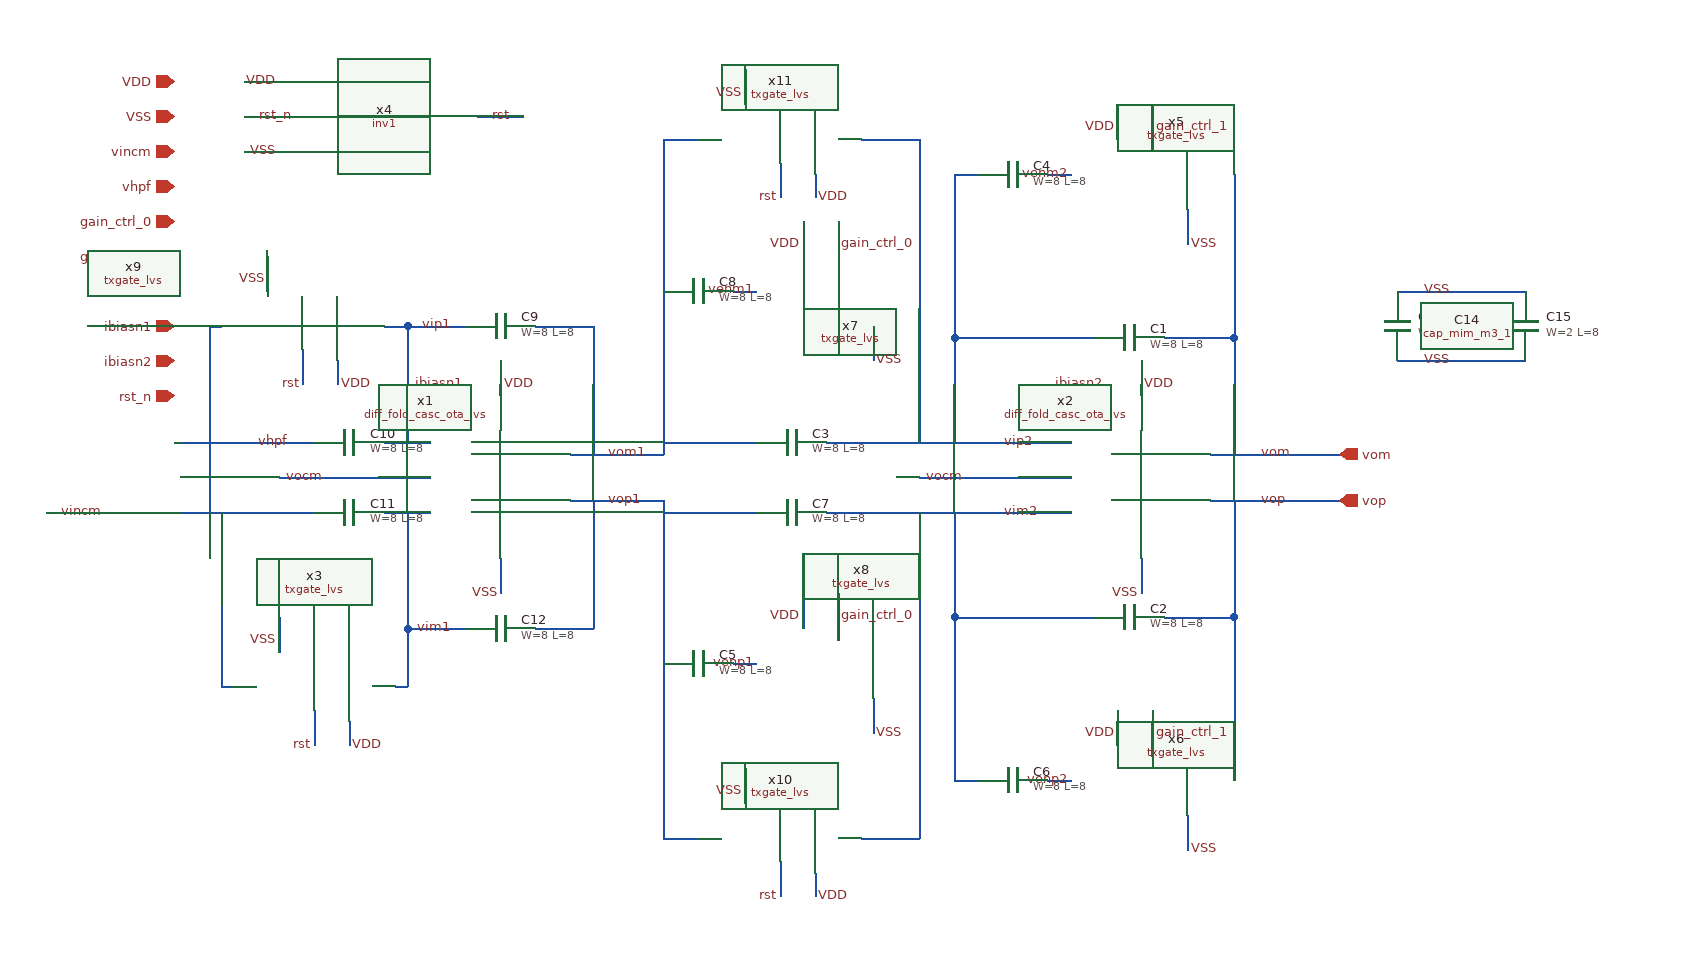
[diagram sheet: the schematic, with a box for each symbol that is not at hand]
v {xschem version=2.9.9 file_version=1.2 }
G {}
K {}
V {}
S {}
E {}
N 970 -630 1030 -630 { lab=vom}
N 1030 -630 1030 -530 { lab=vom}
N 1010 -490 1120 -490 { lab=vop}
N 1010 -530 1120 -530 { lab=vom}
N 790 -630 910 -630 { lab=vip2}
N 790 -630 790 -540 { lab=vip2}
N 790 -770 810 -770 { lab=vip2}
N 790 -770 790 -630 { lab=vip2}
N 1030 -770 1030 -630 { lab=vom}
N 680 -540 890 -540 { lab=vip2}
N 760 -670 760 -540 { lab=vip2}
N 970 -390 1030 -390 { lab=vop}
N 1030 -490 1030 -390 { lab=vop}
N 790 -390 910 -390 { lab=vim2}
N 790 -480 790 -390 { lab=vim2}
N 790 -250 810 -250 { lab=vim2}
N 790 -390 790 -250 { lab=vim2}
N 1030 -390 1030 -250 { lab=vop}
N 680 -480 890 -480 { lab=vim2}
N 760 -480 760 -350 { lab=vim2}
N 300 -540 340 -540 { lab=vip1}
N 300 -480 340 -480 { lab=vim1}
N 320 -480 320 -380 { lab=vim1}
N 320 -380 370 -380 { lab=vim1}
N 320 -640 320 -540 { lab=vip1}
N 320 -640 370 -640 { lab=vip1}
N 210 -510 340 -510 { lab=vocm}
N 430 -640 480 -640 { lab=vom1}
N 480 -640 480 -530 { lab=vom1}
N 430 -380 480 -380 { lab=vop1}
N 480 -490 480 -380 { lab=vop1}
N 460 -530 540 -530 { lab=vom1}
N 460 -490 540 -490 { lab=vop1}
N 120 -540 240 -540 { lab=vhpf}
N 10 -480 240 -480 { lab=vincm}
N 760 -510 890 -510 { lab=vocm}
N 540 -540 620 -540 { lab=vom1}
N 540 -480 620 -480 { lab=vop1}
N 540 -670 540 -530 { lab=vom1}
N 540 -490 540 -350 { lab=vop1}
N 870 -770 890 -770 { lab=venm2}
N 960 -830 960 -790 { lab=gain_ctrl_1}
N 990 -740 990 -710 { lab=VSS}
N 930 -830 930 -800 { lab=VDD}
N 870 -250 890 -250 { lab=venp2}
N 960 -310 960 -270 { lab=gain_ctrl_1}
N 990 -220 990 -190 { lab=VSS}
N 930 -310 930 -280 { lab=VDD}
N 690 -730 690 -690 { lab=gain_ctrl_0}
N 720 -640 720 -610 { lab=VSS}
N 660 -730 660 -700 { lab=VDD}
N 600 -670 620 -670 { lab=venm1}
N 690 -410 690 -370 { lab=gain_ctrl_0}
N 720 -320 720 -290 { lab=VSS}
N 660 -410 660 -380 { lab=VDD}
N 600 -350 620 -350 { lab=venp1}
N 330 -590 370 -590 { lab=ibiasn1}
N 400 -610 400 -580 { lab=VDD}
N 400 -440 400 -410 { lab=VSS}
N 880 -590 920 -590 { lab=ibiasn2}
N 950 -610 950 -580 { lab=VDD}
N 950 -440 950 -410 { lab=VSS}
N 1170 -670 1280 -670 { lab=VSS}
N 1170 -610 1280 -610 { lab=VSS}
N 310 -330 320 -330 { lab=vim1}
N 160 -330 170 -330 { lab=vincm}
N 210 -390 210 -360 { lab=VSS}
N 270 -300 270 -280 { lab=VDD}
N 240 -310 240 -280 { lab=rst}
N 380 -820 420 -820 { lab=rst}
N 180 -850 220 -850 { lab=VDD}
N 180 -790 220 -790 { lab=VSS}
N 180 -820 220 -820 { lab=rst_n}
N 320 -380 320 -330 { lab=vim1}
N 160 -480 160 -330 { lab=vincm}
N 300 -640 310 -640 { lab=vip1}
N 150 -640 160 -640 { lab=vincm}
N 200 -700 200 -670 { lab=VSS}
N 260 -610 260 -590 { lab=VDD}
N 230 -620 230 -590 { lab=rst}
N 310 -640 320 -640 { lab=vip1}
N 150 -640 150 -480 { lab=vincm}
N 710 -200 720 -200 { lab=vim2}
N 560 -200 570 -200 { lab=vop1}
N 610 -260 610 -230 { lab=VSS}
N 670 -170 670 -150 { lab=VDD}
N 640 -180 640 -150 { lab=rst}
N 720 -200 730 -200 { lab=vim2}
N 730 -200 760 -200 { lab=vim2}
N 760 -350 760 -200 { lab=vim2}
N 540 -200 560 -200 { lab=vop1}
N 540 -350 540 -200 { lab=vop1}
N 710 -800 720 -800 { lab=vip2}
N 560 -800 570 -800 { lab=vom1}
N 610 -860 610 -830 { lab=VSS}
N 670 -770 670 -750 { lab=VDD}
N 640 -780 640 -750 { lab=rst}
N 720 -800 730 -800 { lab=vip2}
N 730 -800 760 -800 { lab=vip2}
N 760 -800 760 -670 { lab=vip2}
N 540 -800 560 -800 { lab=vom1}
N 540 -800 540 -670 { lab=vom1}
C {devices/title.sym} 160 -30 0 0 {name=l1 author="Nikhil Poole"}
C {devices/lab_wire.sym} 1050 -530 0 1 {name=l7 sig_type=std_logic lab=vom}
C {devices/lab_wire.sym} 1050 -490 0 1 {name=l8 sig_type=std_logic lab=vop}
C {devices/lab_wire.sym} 360 -640 0 0 {name=l4 sig_type=std_logic lab=vip1}
C {devices/lab_wire.sym} 360 -380 2 1 {name=l5 sig_type=std_logic lab=vim1}
C {devices/lab_wire.sym} 60 -480 0 0 {name=l3 sig_type=std_logic lab=vincm}
C {devices/lab_wire.sym} 490 -530 0 1 {name=l30 sig_type=std_logic lab=vom1}
C {devices/lab_wire.sym} 490 -490 0 1 {name=l31 sig_type=std_logic lab=vop1}
C {devices/lab_wire.sym} 250 -510 0 0 {name=l33 sig_type=std_logic lab=vocm}
C {devices/lab_wire.sym} 800 -510 0 0 {name=l2 sig_type=std_logic lab=vocm}
C {devices/lab_wire.sym} 220 -540 0 0 {name=l29 sig_type=std_logic lab=vhpf}
C {devices/lab_wire.sym} 830 -480 0 1 {name=l34 sig_type=std_logic lab=vim2}
C {devices/lab_wire.sym} 830 -540 0 1 {name=l35 sig_type=std_logic lab=vip2}
C {/home/users/nhpoole/ee272b/ee272b_mixed_signal_mmwave_accelerator/designs/txgate_lvs.sym} 960 -770 0 0 {name=x5}
C {devices/lab_wire.sym} 890 -770 0 0 {name=l25 sig_type=std_logic lab=venm2}
C {devices/lab_wire.sym} 960 -810 0 1 {name=l27 sig_type=std_logic lab=gain_ctrl_1}
C {devices/lab_wire.sym} 990 -710 0 1 {name=l39 sig_type=std_logic lab=VSS}
C {devices/lab_wire.sym} 930 -810 0 0 {name=l40 sig_type=std_logic lab=VDD}
C {/home/users/nhpoole/ee272b/ee272b_mixed_signal_mmwave_accelerator/designs/txgate_lvs.sym} 960 -250 0 0 {name=x6}
C {devices/lab_wire.sym} 890 -250 0 0 {name=l12 sig_type=std_logic lab=venp2}
C {devices/lab_wire.sym} 960 -290 0 1 {name=l14 sig_type=std_logic lab=gain_ctrl_1}
C {devices/lab_wire.sym} 990 -190 0 1 {name=l26 sig_type=std_logic lab=VSS}
C {devices/lab_wire.sym} 930 -290 0 0 {name=l28 sig_type=std_logic lab=VDD}
C {/home/users/nhpoole/ee272b/ee272b_mixed_signal_mmwave_accelerator/designs/txgate_lvs.sym} 690 -670 0 0 {name=x7}
C {devices/lab_wire.sym} 690 -710 0 1 {name=l6 sig_type=std_logic lab=gain_ctrl_0}
C {devices/lab_wire.sym} 720 -610 0 1 {name=l11 sig_type=std_logic lab=VSS}
C {devices/lab_wire.sym} 660 -710 0 0 {name=l19 sig_type=std_logic lab=VDD}
C {devices/lab_wire.sym} 620 -670 0 0 {name=l20 sig_type=std_logic lab=venm1}
C {/home/users/nhpoole/ee272b/ee272b_mixed_signal_mmwave_accelerator/designs/txgate_lvs.sym} 690 -350 0 0 {name=x8}
C {devices/lab_wire.sym} 690 -390 0 1 {name=l15 sig_type=std_logic lab=gain_ctrl_0}
C {devices/lab_wire.sym} 720 -290 0 1 {name=l16 sig_type=std_logic lab=VSS}
C {devices/lab_wire.sym} 660 -390 0 0 {name=l21 sig_type=std_logic lab=VDD}
C {devices/lab_wire.sym} 620 -350 0 0 {name=l22 sig_type=std_logic lab=venp1}
C {devices/ipin.sym} 120 -850 0 0 {name=p1 lab=VDD}
C {devices/ipin.sym} 120 -820 0 0 {name=p2 lab=VSS}
C {devices/ipin.sym} 120 -790 0 0 {name=p3 lab=vincm}
C {devices/ipin.sym} 120 -760 0 0 {name=p4 lab=vhpf}
C {devices/ipin.sym} 120 -730 0 0 {name=p5 lab=gain_ctrl_0}
C {devices/ipin.sym} 120 -700 0 0 {name=p6 lab=gain_ctrl_1}
C {devices/ipin.sym} 120 -670 0 0 {name=p7 lab=vocm}
C {devices/ipin.sym} 120 -640 0 0 {name=p8 lab=ibiasn1}
C {devices/lab_wire.sym} 370 -590 0 0 {name=l9 sig_type=std_logic lab=ibiasn1}
C {devices/lab_wire.sym} 400 -410 0 0 {name=l13 sig_type=std_logic lab=VSS}
C {devices/lab_wire.sym} 400 -590 0 1 {name=l17 sig_type=std_logic lab=VDD}
C {devices/lab_wire.sym} 920 -590 0 0 {name=l18 sig_type=std_logic lab=ibiasn2}
C {devices/lab_wire.sym} 950 -410 0 0 {name=l23 sig_type=std_logic lab=VSS}
C {devices/lab_wire.sym} 950 -590 0 1 {name=l24 sig_type=std_logic lab=VDD}
C {sky130_fd_pr/cap_mim_m3_1.sym} 940 -630 1 0 {name=C1 model=cap_mim_m3_1 W=8 L=8 MF=2 spiceprefix=X}
C {sky130_fd_pr/cap_mim_m3_1.sym} 940 -390 1 0 {name=C2 model=cap_mim_m3_1 W=8 L=8 MF=2 spiceprefix=X}
C {sky130_fd_pr/cap_mim_m3_1.sym} 840 -770 1 0 {name=C4 model=cap_mim_m3_1 W=8 L=8 MF=6 spiceprefix=X}
C {sky130_fd_pr/cap_mim_m3_1.sym} 840 -250 1 0 {name=C6 model=cap_mim_m3_1 W=8 L=8 MF=6 spiceprefix=X}
C {sky130_fd_pr/cap_mim_m3_1.sym} 570 -350 1 0 {name=C5 model=cap_mim_m3_1 W=8 L=8 MF=4 spiceprefix=X}
C {sky130_fd_pr/cap_mim_m3_1.sym} 650 -480 1 0 {name=C7 model=cap_mim_m3_1 W=8 L=8 MF=4 spiceprefix=X}
C {sky130_fd_pr/cap_mim_m3_1.sym} 650 -540 1 0 {name=C3 model=cap_mim_m3_1 W=8 L=8 MF=4 spiceprefix=X}
C {sky130_fd_pr/cap_mim_m3_1.sym} 570 -670 1 0 {name=C8 model=cap_mim_m3_1 W=8 L=8 MF=4 spiceprefix=X}
C {sky130_fd_pr/cap_mim_m3_1.sym} 400 -640 1 0 {name=C9 model=cap_mim_m3_1 W=8 L=8 MF=4 spiceprefix=X}
C {sky130_fd_pr/cap_mim_m3_1.sym} 270 -540 1 0 {name=C10 model=cap_mim_m3_1 W=8 L=8 MF=4 spiceprefix=X}
C {sky130_fd_pr/cap_mim_m3_1.sym} 270 -480 1 0 {name=C11 model=cap_mim_m3_1 W=8 L=8 MF=4 spiceprefix=X}
C {sky130_fd_pr/cap_mim_m3_1.sym} 400 -380 1 0 {name=C12 model=cap_mim_m3_1 W=8 L=8 MF=4 spiceprefix=X}
C {sky130_fd_pr/cap_mim_m3_1.sym} 1170 -640 0 0 {name=C13 model=cap_mim_m3_1 W=12 L=2 MF=20 spiceprefix=X}
C {sky130_fd_pr/cap_mim_m3_1.sym} 1230 -640 0 0 {name=C14 model=cap_mim_m3_1 W=8 L=2 MF=22 spiceprefix=X}
C {sky130_fd_pr/cap_mim_m3_1.sym} 1280 -640 0 0 {name=C15 model=cap_mim_m3_1 W=2 L=8 MF=24 spiceprefix=X}
C {devices/lab_wire.sym} 1190 -670 0 1 {name=l10 sig_type=std_logic lab=VSS}
C {devices/lab_wire.sym} 1190 -610 2 0 {name=l32 sig_type=std_logic lab=VSS}
C {devices/opin.sym} 1120 -530 0 0 {name=p9 lab=vom}
C {devices/opin.sym} 1120 -490 0 0 {name=p10 lab=vop}
C {/home/users/nhpoole/ee272b/ee272b_mixed_signal_mmwave_accelerator/designs/diff_fold_casc_ota_lvs.sym} 400 -510 0 0 {name=x1}
C {/home/users/nhpoole/ee272b/ee272b_mixed_signal_mmwave_accelerator/designs/diff_fold_casc_ota_lvs.sym} 950 -510 0 0 {name=x2}
C {devices/ipin.sym} 120 -610 0 0 {name=p11 lab=ibiasn2}
C {/home/users/nhpoole/ee272b/ee272b_mixed_signal_mmwave_accelerator/designs/txgate_lvs.sym} 240 -330 2 0 {name=x3}
C {devices/lab_wire.sym} 210 -370 0 0 {name=l36 sig_type=std_logic lab=VSS}
C {devices/lab_wire.sym} 270 -280 0 1 {name=l37 sig_type=std_logic lab=VDD}
C {devices/lab_wire.sym} 240 -280 0 0 {name=l38 sig_type=std_logic lab=rst}
C {/home/users/nhpoole/ee272b/ee272b_mixed_signal_mmwave_accelerator/designs/inv1.sym} 270 -820 0 0 {name=x4}
C {devices/lab_wire.sym} 390 -820 0 1 {name=l41 sig_type=std_logic lab=rst}
C {devices/lab_wire.sym} 190 -820 0 1 {name=l42 sig_type=std_logic lab=rst_n}
C {devices/lab_wire.sym} 210 -850 0 0 {name=l43 sig_type=std_logic lab=VDD}
C {devices/lab_wire.sym} 210 -790 0 0 {name=l44 sig_type=std_logic lab=VSS}
C {devices/ipin.sym} 120 -580 0 0 {name=p12 lab=rst_n}
C {/home/users/nhpoole/ee272b/ee272b_mixed_signal_mmwave_accelerator/designs/txgate_lvs.sym} 230 -640 2 0 {name=x9}
C {devices/lab_wire.sym} 200 -680 0 0 {name=l45 sig_type=std_logic lab=VSS}
C {devices/lab_wire.sym} 260 -590 0 1 {name=l46 sig_type=std_logic lab=VDD}
C {devices/lab_wire.sym} 230 -590 0 0 {name=l47 sig_type=std_logic lab=rst}
C {/home/users/nhpoole/ee272b/ee272b_mixed_signal_mmwave_accelerator/designs/txgate_lvs.sym} 640 -200 2 0 {name=x10}
C {devices/lab_wire.sym} 610 -240 0 0 {name=l48 sig_type=std_logic lab=VSS}
C {devices/lab_wire.sym} 670 -150 0 1 {name=l49 sig_type=std_logic lab=VDD}
C {devices/lab_wire.sym} 640 -150 0 0 {name=l50 sig_type=std_logic lab=rst}
C {/home/users/nhpoole/ee272b/ee272b_mixed_signal_mmwave_accelerator/designs/txgate_lvs.sym} 640 -800 2 0 {name=x11}
C {devices/lab_wire.sym} 610 -840 0 0 {name=l51 sig_type=std_logic lab=VSS}
C {devices/lab_wire.sym} 670 -750 0 1 {name=l52 sig_type=std_logic lab=VDD}
C {devices/lab_wire.sym} 640 -750 0 0 {name=l53 sig_type=std_logic lab=rst}
